VERSION 5.7 ;
  NOWIREEXTENSIONATPIN ON ;
  DIVIDERCHAR "/" ;
  BUSBITCHARS "[]" ;
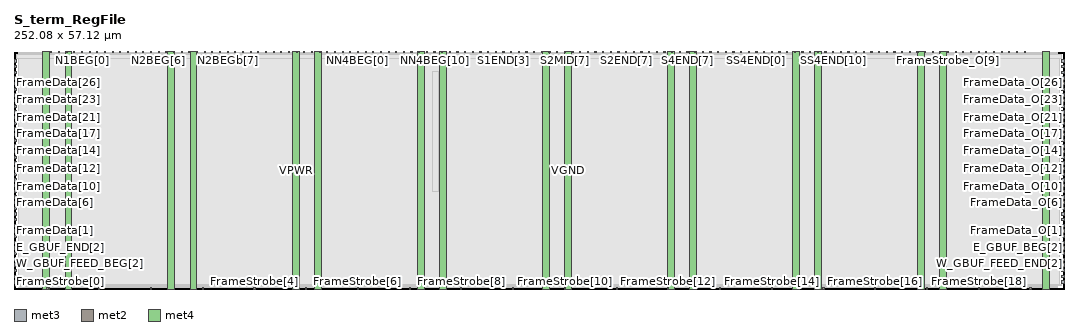
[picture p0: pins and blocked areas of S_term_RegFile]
MACRO S_term_RegFile
  CLASS BLOCK ;
  FOREIGN S_term_RegFile ;
  ORIGIN 0.000 0.000 ;
  SIZE 252.080 BY 57.120 ;
  PIN E_GBUF_BEG[0]
    DIRECTION OUTPUT ;
    USE SIGNAL ;
    ANTENNADIFFAREA 0.702900 ;
    PORT
      LAYER met3 ;
        RECT 251.480 6.840 252.080 7.440 ;
    END
  END E_GBUF_BEG[0]
  PIN E_GBUF_BEG[1]
    DIRECTION OUTPUT ;
    USE SIGNAL ;
    ANTENNADIFFAREA 0.702900 ;
    PORT
      LAYER met3 ;
        RECT 251.480 8.200 252.080 8.800 ;
    END
  END E_GBUF_BEG[1]
  PIN E_GBUF_BEG[2]
    DIRECTION OUTPUT ;
    USE SIGNAL ;
    ANTENNADIFFAREA 0.702900 ;
    PORT
      LAYER met3 ;
        RECT 251.480 9.560 252.080 10.160 ;
    END
  END E_GBUF_BEG[2]
  PIN E_GBUF_BEG[3]
    DIRECTION OUTPUT ;
    USE SIGNAL ;
    ANTENNADIFFAREA 0.702900 ;
    PORT
      LAYER met3 ;
        RECT 251.480 10.920 252.080 11.520 ;
    END
  END E_GBUF_BEG[3]
  PIN E_GBUF_END[0]
    DIRECTION INPUT ;
    USE SIGNAL ;
    ANTENNAGATEAREA 0.318000 ;
    PORT
      LAYER met3 ;
        RECT 0.000 6.840 0.600 7.440 ;
    END
  END E_GBUF_END[0]
  PIN E_GBUF_END[1]
    DIRECTION INPUT ;
    USE SIGNAL ;
    ANTENNAGATEAREA 0.318000 ;
    PORT
      LAYER met3 ;
        RECT 0.000 8.200 0.600 8.800 ;
    END
  END E_GBUF_END[1]
  PIN E_GBUF_END[2]
    DIRECTION INPUT ;
    USE SIGNAL ;
    ANTENNAGATEAREA 0.318000 ;
    PORT
      LAYER met3 ;
        RECT 0.000 9.560 0.600 10.160 ;
    END
  END E_GBUF_END[2]
  PIN E_GBUF_END[3]
    DIRECTION INPUT ;
    USE SIGNAL ;
    ANTENNAGATEAREA 0.318000 ;
    PORT
      LAYER met3 ;
        RECT 0.000 10.920 0.600 11.520 ;
    END
  END E_GBUF_END[3]
  PIN FrameData[0]
    DIRECTION INPUT ;
    USE SIGNAL ;
    ANTENNAGATEAREA 0.159000 ;
    PORT
      LAYER met3 ;
        RECT 0.000 12.280 0.600 12.880 ;
    END
  END FrameData[0]
  PIN FrameData[10]
    DIRECTION INPUT ;
    USE SIGNAL ;
    ANTENNAGATEAREA 0.159000 ;
    PORT
      LAYER met3 ;
        RECT 0.000 25.880 0.600 26.480 ;
    END
  END FrameData[10]
  PIN FrameData[11]
    DIRECTION INPUT ;
    USE SIGNAL ;
    ANTENNAGATEAREA 0.159000 ;
    PORT
      LAYER met3 ;
        RECT 0.000 27.240 0.600 27.840 ;
    END
  END FrameData[11]
  PIN FrameData[12]
    DIRECTION INPUT ;
    USE SIGNAL ;
    ANTENNAGATEAREA 0.159000 ;
    PORT
      LAYER met3 ;
        RECT 0.000 28.600 0.600 29.200 ;
    END
  END FrameData[12]
  PIN FrameData[13]
    DIRECTION INPUT ;
    USE SIGNAL ;
    ANTENNAGATEAREA 0.159000 ;
    PORT
      LAYER met3 ;
        RECT 0.000 29.960 0.600 30.560 ;
    END
  END FrameData[13]
  PIN FrameData[14]
    DIRECTION INPUT ;
    USE SIGNAL ;
    ANTENNAGATEAREA 0.159000 ;
    PORT
      LAYER met3 ;
        RECT 0.000 31.320 0.600 31.920 ;
    END
  END FrameData[14]
  PIN FrameData[15]
    DIRECTION INPUT ;
    USE SIGNAL ;
    ANTENNAGATEAREA 0.159000 ;
    PORT
      LAYER met3 ;
        RECT 0.000 32.680 0.600 33.280 ;
    END
  END FrameData[15]
  PIN FrameData[16]
    DIRECTION INPUT ;
    USE SIGNAL ;
    ANTENNAGATEAREA 0.159000 ;
    PORT
      LAYER met3 ;
        RECT 0.000 34.040 0.600 34.640 ;
    END
  END FrameData[16]
  PIN FrameData[17]
    DIRECTION INPUT ;
    USE SIGNAL ;
    ANTENNAGATEAREA 0.159000 ;
    PORT
      LAYER met3 ;
        RECT 0.000 35.400 0.600 36.000 ;
    END
  END FrameData[17]
  PIN FrameData[18]
    DIRECTION INPUT ;
    USE SIGNAL ;
    ANTENNAGATEAREA 0.159000 ;
    PORT
      LAYER met3 ;
        RECT 0.000 36.760 0.600 37.360 ;
    END
  END FrameData[18]
  PIN FrameData[19]
    DIRECTION INPUT ;
    USE SIGNAL ;
    ANTENNAGATEAREA 0.159000 ;
    PORT
      LAYER met3 ;
        RECT 0.000 38.120 0.600 38.720 ;
    END
  END FrameData[19]
  PIN FrameData[1]
    DIRECTION INPUT ;
    USE SIGNAL ;
    ANTENNAGATEAREA 0.159000 ;
    PORT
      LAYER met3 ;
        RECT 0.000 13.640 0.600 14.240 ;
    END
  END FrameData[1]
  PIN FrameData[20]
    DIRECTION INPUT ;
    USE SIGNAL ;
    ANTENNAGATEAREA 0.159000 ;
    PORT
      LAYER met3 ;
        RECT 0.000 39.480 0.600 40.080 ;
    END
  END FrameData[20]
  PIN FrameData[21]
    DIRECTION INPUT ;
    USE SIGNAL ;
    ANTENNAGATEAREA 0.159000 ;
    PORT
      LAYER met3 ;
        RECT 0.000 40.840 0.600 41.440 ;
    END
  END FrameData[21]
  PIN FrameData[22]
    DIRECTION INPUT ;
    USE SIGNAL ;
    ANTENNAGATEAREA 0.159000 ;
    PORT
      LAYER met3 ;
        RECT 0.000 42.200 0.600 42.800 ;
    END
  END FrameData[22]
  PIN FrameData[23]
    DIRECTION INPUT ;
    USE SIGNAL ;
    ANTENNAGATEAREA 0.159000 ;
    PORT
      LAYER met3 ;
        RECT 0.000 43.560 0.600 44.160 ;
    END
  END FrameData[23]
  PIN FrameData[24]
    DIRECTION INPUT ;
    USE SIGNAL ;
    ANTENNAGATEAREA 1.187400 ;
    ANTENNADIFFAREA 0.869400 ;
    PORT
      LAYER met3 ;
        RECT 0.000 44.920 0.600 45.520 ;
    END
  END FrameData[24]
  PIN FrameData[25]
    DIRECTION INPUT ;
    USE SIGNAL ;
    ANTENNAGATEAREA 1.187400 ;
    ANTENNADIFFAREA 0.869400 ;
    PORT
      LAYER met3 ;
        RECT 0.000 46.280 0.600 46.880 ;
    END
  END FrameData[25]
  PIN FrameData[26]
    DIRECTION INPUT ;
    USE SIGNAL ;
    ANTENNAGATEAREA 1.187400 ;
    ANTENNADIFFAREA 0.869400 ;
    PORT
      LAYER met3 ;
        RECT 0.000 47.640 0.600 48.240 ;
    END
  END FrameData[26]
  PIN FrameData[27]
    DIRECTION INPUT ;
    USE SIGNAL ;
    ANTENNAGATEAREA 1.187400 ;
    ANTENNADIFFAREA 0.869400 ;
    PORT
      LAYER met3 ;
        RECT 0.000 49.000 0.600 49.600 ;
    END
  END FrameData[27]
  PIN FrameData[28]
    DIRECTION INPUT ;
    USE SIGNAL ;
    ANTENNAGATEAREA 1.187400 ;
    ANTENNADIFFAREA 0.869400 ;
    PORT
      LAYER met3 ;
        RECT 0.000 50.360 0.600 50.960 ;
    END
  END FrameData[28]
  PIN FrameData[29]
    DIRECTION INPUT ;
    USE SIGNAL ;
    ANTENNAGATEAREA 1.187400 ;
    ANTENNADIFFAREA 0.869400 ;
    PORT
      LAYER met3 ;
        RECT 0.000 51.720 0.600 52.320 ;
    END
  END FrameData[29]
  PIN FrameData[2]
    DIRECTION INPUT ;
    USE SIGNAL ;
    ANTENNAGATEAREA 0.159000 ;
    PORT
      LAYER met3 ;
        RECT 0.000 15.000 0.600 15.600 ;
    END
  END FrameData[2]
  PIN FrameData[30]
    DIRECTION INPUT ;
    USE SIGNAL ;
    ANTENNAGATEAREA 0.318000 ;
    PORT
      LAYER met3 ;
        RECT 0.000 53.080 0.600 53.680 ;
    END
  END FrameData[30]
  PIN FrameData[31]
    DIRECTION INPUT ;
    USE SIGNAL ;
    ANTENNAGATEAREA 0.752700 ;
    ANTENNADIFFAREA 0.434700 ;
    PORT
      LAYER met3 ;
        RECT 0.000 54.440 0.600 55.040 ;
    END
  END FrameData[31]
  PIN FrameData[3]
    DIRECTION INPUT ;
    USE SIGNAL ;
    ANTENNAGATEAREA 0.159000 ;
    PORT
      LAYER met3 ;
        RECT 0.000 16.360 0.600 16.960 ;
    END
  END FrameData[3]
  PIN FrameData[4]
    DIRECTION INPUT ;
    USE SIGNAL ;
    ANTENNAGATEAREA 0.159000 ;
    PORT
      LAYER met3 ;
        RECT 0.000 17.720 0.600 18.320 ;
    END
  END FrameData[4]
  PIN FrameData[5]
    DIRECTION INPUT ;
    USE SIGNAL ;
    ANTENNAGATEAREA 0.159000 ;
    PORT
      LAYER met3 ;
        RECT 0.000 19.080 0.600 19.680 ;
    END
  END FrameData[5]
  PIN FrameData[6]
    DIRECTION INPUT ;
    USE SIGNAL ;
    ANTENNAGATEAREA 0.159000 ;
    PORT
      LAYER met3 ;
        RECT 0.000 20.440 0.600 21.040 ;
    END
  END FrameData[6]
  PIN FrameData[7]
    DIRECTION INPUT ;
    USE SIGNAL ;
    ANTENNAGATEAREA 0.159000 ;
    PORT
      LAYER met3 ;
        RECT 0.000 21.800 0.600 22.400 ;
    END
  END FrameData[7]
  PIN FrameData[8]
    DIRECTION INPUT ;
    USE SIGNAL ;
    ANTENNAGATEAREA 0.159000 ;
    PORT
      LAYER met3 ;
        RECT 0.000 23.160 0.600 23.760 ;
    END
  END FrameData[8]
  PIN FrameData[9]
    DIRECTION INPUT ;
    USE SIGNAL ;
    ANTENNAGATEAREA 0.159000 ;
    PORT
      LAYER met3 ;
        RECT 0.000 24.520 0.600 25.120 ;
    END
  END FrameData[9]
  PIN FrameData_O[0]
    DIRECTION OUTPUT ;
    USE SIGNAL ;
    ANTENNADIFFAREA 0.702900 ;
    PORT
      LAYER met3 ;
        RECT 251.480 12.280 252.080 12.880 ;
    END
  END FrameData_O[0]
  PIN FrameData_O[10]
    DIRECTION OUTPUT ;
    USE SIGNAL ;
    ANTENNADIFFAREA 0.702900 ;
    PORT
      LAYER met3 ;
        RECT 251.480 25.880 252.080 26.480 ;
    END
  END FrameData_O[10]
  PIN FrameData_O[11]
    DIRECTION OUTPUT ;
    USE SIGNAL ;
    ANTENNADIFFAREA 0.702900 ;
    PORT
      LAYER met3 ;
        RECT 251.480 27.240 252.080 27.840 ;
    END
  END FrameData_O[11]
  PIN FrameData_O[12]
    DIRECTION OUTPUT ;
    USE SIGNAL ;
    ANTENNADIFFAREA 0.702900 ;
    PORT
      LAYER met3 ;
        RECT 251.480 28.600 252.080 29.200 ;
    END
  END FrameData_O[12]
  PIN FrameData_O[13]
    DIRECTION OUTPUT ;
    USE SIGNAL ;
    ANTENNADIFFAREA 0.702900 ;
    PORT
      LAYER met3 ;
        RECT 251.480 29.960 252.080 30.560 ;
    END
  END FrameData_O[13]
  PIN FrameData_O[14]
    DIRECTION OUTPUT ;
    USE SIGNAL ;
    ANTENNADIFFAREA 0.702900 ;
    PORT
      LAYER met3 ;
        RECT 251.480 31.320 252.080 31.920 ;
    END
  END FrameData_O[14]
  PIN FrameData_O[15]
    DIRECTION OUTPUT ;
    USE SIGNAL ;
    ANTENNADIFFAREA 0.702900 ;
    PORT
      LAYER met3 ;
        RECT 251.480 32.680 252.080 33.280 ;
    END
  END FrameData_O[15]
  PIN FrameData_O[16]
    DIRECTION OUTPUT ;
    USE SIGNAL ;
    ANTENNADIFFAREA 0.702900 ;
    PORT
      LAYER met3 ;
        RECT 251.480 34.040 252.080 34.640 ;
    END
  END FrameData_O[16]
  PIN FrameData_O[17]
    DIRECTION OUTPUT ;
    USE SIGNAL ;
    ANTENNADIFFAREA 0.702900 ;
    PORT
      LAYER met3 ;
        RECT 251.480 35.400 252.080 36.000 ;
    END
  END FrameData_O[17]
  PIN FrameData_O[18]
    DIRECTION OUTPUT ;
    USE SIGNAL ;
    ANTENNADIFFAREA 0.702900 ;
    PORT
      LAYER met3 ;
        RECT 251.480 36.760 252.080 37.360 ;
    END
  END FrameData_O[18]
  PIN FrameData_O[19]
    DIRECTION OUTPUT ;
    USE SIGNAL ;
    ANTENNADIFFAREA 0.702900 ;
    PORT
      LAYER met3 ;
        RECT 251.480 38.120 252.080 38.720 ;
    END
  END FrameData_O[19]
  PIN FrameData_O[1]
    DIRECTION OUTPUT ;
    USE SIGNAL ;
    ANTENNADIFFAREA 0.702900 ;
    PORT
      LAYER met3 ;
        RECT 251.480 13.640 252.080 14.240 ;
    END
  END FrameData_O[1]
  PIN FrameData_O[20]
    DIRECTION OUTPUT ;
    USE SIGNAL ;
    ANTENNADIFFAREA 0.702900 ;
    PORT
      LAYER met3 ;
        RECT 251.480 39.480 252.080 40.080 ;
    END
  END FrameData_O[20]
  PIN FrameData_O[21]
    DIRECTION OUTPUT ;
    USE SIGNAL ;
    ANTENNADIFFAREA 0.702900 ;
    PORT
      LAYER met3 ;
        RECT 251.480 40.840 252.080 41.440 ;
    END
  END FrameData_O[21]
  PIN FrameData_O[22]
    DIRECTION OUTPUT ;
    USE SIGNAL ;
    ANTENNADIFFAREA 0.702900 ;
    PORT
      LAYER met3 ;
        RECT 251.480 42.200 252.080 42.800 ;
    END
  END FrameData_O[22]
  PIN FrameData_O[23]
    DIRECTION OUTPUT ;
    USE SIGNAL ;
    ANTENNADIFFAREA 0.702900 ;
    PORT
      LAYER met3 ;
        RECT 251.480 43.560 252.080 44.160 ;
    END
  END FrameData_O[23]
  PIN FrameData_O[24]
    DIRECTION OUTPUT ;
    USE SIGNAL ;
    ANTENNADIFFAREA 0.702900 ;
    PORT
      LAYER met3 ;
        RECT 251.480 44.920 252.080 45.520 ;
    END
  END FrameData_O[24]
  PIN FrameData_O[25]
    DIRECTION OUTPUT ;
    USE SIGNAL ;
    ANTENNADIFFAREA 0.702900 ;
    PORT
      LAYER met3 ;
        RECT 251.480 46.280 252.080 46.880 ;
    END
  END FrameData_O[25]
  PIN FrameData_O[26]
    DIRECTION OUTPUT ;
    USE SIGNAL ;
    ANTENNADIFFAREA 0.702900 ;
    PORT
      LAYER met3 ;
        RECT 251.480 47.640 252.080 48.240 ;
    END
  END FrameData_O[26]
  PIN FrameData_O[27]
    DIRECTION OUTPUT ;
    USE SIGNAL ;
    ANTENNADIFFAREA 0.702900 ;
    PORT
      LAYER met3 ;
        RECT 251.480 49.000 252.080 49.600 ;
    END
  END FrameData_O[27]
  PIN FrameData_O[28]
    DIRECTION OUTPUT ;
    USE SIGNAL ;
    ANTENNADIFFAREA 0.702900 ;
    PORT
      LAYER met3 ;
        RECT 251.480 50.360 252.080 50.960 ;
    END
  END FrameData_O[28]
  PIN FrameData_O[29]
    DIRECTION OUTPUT ;
    USE SIGNAL ;
    ANTENNADIFFAREA 0.702900 ;
    PORT
      LAYER met3 ;
        RECT 251.480 51.720 252.080 52.320 ;
    END
  END FrameData_O[29]
  PIN FrameData_O[2]
    DIRECTION OUTPUT ;
    USE SIGNAL ;
    ANTENNADIFFAREA 0.702900 ;
    PORT
      LAYER met3 ;
        RECT 251.480 15.000 252.080 15.600 ;
    END
  END FrameData_O[2]
  PIN FrameData_O[30]
    DIRECTION OUTPUT ;
    USE SIGNAL ;
    ANTENNADIFFAREA 0.702900 ;
    PORT
      LAYER met3 ;
        RECT 251.480 53.080 252.080 53.680 ;
    END
  END FrameData_O[30]
  PIN FrameData_O[31]
    DIRECTION OUTPUT ;
    USE SIGNAL ;
    ANTENNADIFFAREA 0.702900 ;
    PORT
      LAYER met3 ;
        RECT 251.480 54.440 252.080 55.040 ;
    END
  END FrameData_O[31]
  PIN FrameData_O[3]
    DIRECTION OUTPUT ;
    USE SIGNAL ;
    ANTENNADIFFAREA 0.702900 ;
    PORT
      LAYER met3 ;
        RECT 251.480 16.360 252.080 16.960 ;
    END
  END FrameData_O[3]
  PIN FrameData_O[4]
    DIRECTION OUTPUT ;
    USE SIGNAL ;
    ANTENNADIFFAREA 0.702900 ;
    PORT
      LAYER met3 ;
        RECT 251.480 17.720 252.080 18.320 ;
    END
  END FrameData_O[4]
  PIN FrameData_O[5]
    DIRECTION OUTPUT ;
    USE SIGNAL ;
    ANTENNADIFFAREA 0.702900 ;
    PORT
      LAYER met3 ;
        RECT 251.480 19.080 252.080 19.680 ;
    END
  END FrameData_O[5]
  PIN FrameData_O[6]
    DIRECTION OUTPUT ;
    USE SIGNAL ;
    ANTENNADIFFAREA 0.702900 ;
    PORT
      LAYER met3 ;
        RECT 251.480 20.440 252.080 21.040 ;
    END
  END FrameData_O[6]
  PIN FrameData_O[7]
    DIRECTION OUTPUT ;
    USE SIGNAL ;
    ANTENNADIFFAREA 0.702900 ;
    PORT
      LAYER met3 ;
        RECT 251.480 21.800 252.080 22.400 ;
    END
  END FrameData_O[7]
  PIN FrameData_O[8]
    DIRECTION OUTPUT ;
    USE SIGNAL ;
    ANTENNADIFFAREA 0.702900 ;
    PORT
      LAYER met3 ;
        RECT 251.480 23.160 252.080 23.760 ;
    END
  END FrameData_O[8]
  PIN FrameData_O[9]
    DIRECTION OUTPUT ;
    USE SIGNAL ;
    ANTENNADIFFAREA 0.702900 ;
    PORT
      LAYER met3 ;
        RECT 251.480 24.520 252.080 25.120 ;
    END
  END FrameData_O[9]
  PIN FrameStrobe[0]
    DIRECTION INPUT ;
    USE SIGNAL ;
    ANTENNAGATEAREA 1.865700 ;
    ANTENNADIFFAREA 0.434700 ;
    PORT
      LAYER met2 ;
        RECT 7.910 0.000 8.190 0.280 ;
    END
  END FrameStrobe[0]
  PIN FrameStrobe[10]
    DIRECTION INPUT ;
    USE SIGNAL ;
    ANTENNAGATEAREA 0.159000 ;
    PORT
      LAYER met2 ;
        RECT 132.110 0.000 132.390 0.280 ;
    END
  END FrameStrobe[10]
  PIN FrameStrobe[11]
    DIRECTION INPUT ;
    USE SIGNAL ;
    ANTENNAGATEAREA 0.159000 ;
    PORT
      LAYER met2 ;
        RECT 144.530 0.000 144.810 0.280 ;
    END
  END FrameStrobe[11]
  PIN FrameStrobe[12]
    DIRECTION INPUT ;
    USE SIGNAL ;
    ANTENNAGATEAREA 0.159000 ;
    PORT
      LAYER met2 ;
        RECT 156.950 0.000 157.230 0.280 ;
    END
  END FrameStrobe[12]
  PIN FrameStrobe[13]
    DIRECTION INPUT ;
    USE SIGNAL ;
    ANTENNAGATEAREA 0.159000 ;
    PORT
      LAYER met2 ;
        RECT 169.370 0.000 169.650 0.280 ;
    END
  END FrameStrobe[13]
  PIN FrameStrobe[14]
    DIRECTION INPUT ;
    USE SIGNAL ;
    ANTENNAGATEAREA 0.159000 ;
    PORT
      LAYER met2 ;
        RECT 181.790 0.000 182.070 0.280 ;
    END
  END FrameStrobe[14]
  PIN FrameStrobe[15]
    DIRECTION INPUT ;
    USE SIGNAL ;
    ANTENNAGATEAREA 0.159000 ;
    PORT
      LAYER met2 ;
        RECT 194.210 0.000 194.490 0.280 ;
    END
  END FrameStrobe[15]
  PIN FrameStrobe[16]
    DIRECTION INPUT ;
    USE SIGNAL ;
    ANTENNAGATEAREA 0.159000 ;
    PORT
      LAYER met2 ;
        RECT 206.630 0.000 206.910 0.280 ;
    END
  END FrameStrobe[16]
  PIN FrameStrobe[17]
    DIRECTION INPUT ;
    USE SIGNAL ;
    ANTENNAGATEAREA 0.159000 ;
    PORT
      LAYER met2 ;
        RECT 219.050 0.000 219.330 0.280 ;
    END
  END FrameStrobe[17]
  PIN FrameStrobe[18]
    DIRECTION INPUT ;
    USE SIGNAL ;
    ANTENNAGATEAREA 0.159000 ;
    PORT
      LAYER met2 ;
        RECT 231.470 0.000 231.750 0.280 ;
    END
  END FrameStrobe[18]
  PIN FrameStrobe[19]
    DIRECTION INPUT ;
    USE SIGNAL ;
    ANTENNAGATEAREA 0.159000 ;
    PORT
      LAYER met2 ;
        RECT 243.890 0.000 244.170 0.280 ;
    END
  END FrameStrobe[19]
  PIN FrameStrobe[1]
    DIRECTION INPUT ;
    USE SIGNAL ;
    ANTENNAGATEAREA 0.159000 ;
    PORT
      LAYER met2 ;
        RECT 20.330 0.000 20.610 0.280 ;
    END
  END FrameStrobe[1]
  PIN FrameStrobe[2]
    DIRECTION INPUT ;
    USE SIGNAL ;
    ANTENNAGATEAREA 0.159000 ;
    PORT
      LAYER met2 ;
        RECT 32.750 0.000 33.030 0.280 ;
    END
  END FrameStrobe[2]
  PIN FrameStrobe[3]
    DIRECTION INPUT ;
    USE SIGNAL ;
    ANTENNAGATEAREA 0.159000 ;
    PORT
      LAYER met2 ;
        RECT 45.170 0.000 45.450 0.280 ;
    END
  END FrameStrobe[3]
  PIN FrameStrobe[4]
    DIRECTION INPUT ;
    USE SIGNAL ;
    ANTENNAGATEAREA 0.593700 ;
    ANTENNADIFFAREA 0.434700 ;
    PORT
      LAYER met2 ;
        RECT 57.590 0.000 57.870 0.280 ;
    END
  END FrameStrobe[4]
  PIN FrameStrobe[5]
    DIRECTION INPUT ;
    USE SIGNAL ;
    ANTENNAGATEAREA 0.159000 ;
    PORT
      LAYER met2 ;
        RECT 70.010 0.000 70.290 0.280 ;
    END
  END FrameStrobe[5]
  PIN FrameStrobe[6]
    DIRECTION INPUT ;
    USE SIGNAL ;
    ANTENNAGATEAREA 0.593700 ;
    ANTENNADIFFAREA 0.434700 ;
    PORT
      LAYER met2 ;
        RECT 82.430 0.000 82.710 0.280 ;
    END
  END FrameStrobe[6]
  PIN FrameStrobe[7]
    DIRECTION INPUT ;
    USE SIGNAL ;
    ANTENNAGATEAREA 0.593700 ;
    ANTENNADIFFAREA 0.434700 ;
    PORT
      LAYER met2 ;
        RECT 94.850 0.000 95.130 0.280 ;
    END
  END FrameStrobe[7]
  PIN FrameStrobe[8]
    DIRECTION INPUT ;
    USE SIGNAL ;
    ANTENNAGATEAREA 0.593700 ;
    ANTENNADIFFAREA 0.434700 ;
    PORT
      LAYER met2 ;
        RECT 107.270 0.000 107.550 0.280 ;
    END
  END FrameStrobe[8]
  PIN FrameStrobe[9]
    DIRECTION INPUT ;
    USE SIGNAL ;
    ANTENNAGATEAREA 0.593700 ;
    ANTENNADIFFAREA 0.434700 ;
    PORT
      LAYER met2 ;
        RECT 119.690 0.000 119.970 0.280 ;
    END
  END FrameStrobe[9]
  PIN FrameStrobe_O[0]
    DIRECTION OUTPUT ;
    USE SIGNAL ;
    ANTENNADIFFAREA 0.702900 ;
    PORT
      LAYER met2 ;
        RECT 207.550 56.840 207.830 57.120 ;
    END
  END FrameStrobe_O[0]
  PIN FrameStrobe_O[10]
    DIRECTION OUTPUT ;
    USE SIGNAL ;
    ANTENNADIFFAREA 0.702900 ;
    PORT
      LAYER met2 ;
        RECT 225.950 56.840 226.230 57.120 ;
    END
  END FrameStrobe_O[10]
  PIN FrameStrobe_O[11]
    DIRECTION OUTPUT ;
    USE SIGNAL ;
    ANTENNADIFFAREA 0.702900 ;
    PORT
      LAYER met2 ;
        RECT 227.790 56.840 228.070 57.120 ;
    END
  END FrameStrobe_O[11]
  PIN FrameStrobe_O[12]
    DIRECTION OUTPUT ;
    USE SIGNAL ;
    ANTENNADIFFAREA 0.702900 ;
    PORT
      LAYER met2 ;
        RECT 229.630 56.840 229.910 57.120 ;
    END
  END FrameStrobe_O[12]
  PIN FrameStrobe_O[13]
    DIRECTION OUTPUT ;
    USE SIGNAL ;
    ANTENNADIFFAREA 0.702900 ;
    PORT
      LAYER met2 ;
        RECT 231.470 56.840 231.750 57.120 ;
    END
  END FrameStrobe_O[13]
  PIN FrameStrobe_O[14]
    DIRECTION OUTPUT ;
    USE SIGNAL ;
    ANTENNADIFFAREA 0.702900 ;
    PORT
      LAYER met2 ;
        RECT 233.310 56.840 233.590 57.120 ;
    END
  END FrameStrobe_O[14]
  PIN FrameStrobe_O[15]
    DIRECTION OUTPUT ;
    USE SIGNAL ;
    ANTENNADIFFAREA 0.702900 ;
    PORT
      LAYER met2 ;
        RECT 235.150 56.840 235.430 57.120 ;
    END
  END FrameStrobe_O[15]
  PIN FrameStrobe_O[16]
    DIRECTION OUTPUT ;
    USE SIGNAL ;
    ANTENNADIFFAREA 0.702900 ;
    PORT
      LAYER met2 ;
        RECT 236.990 56.840 237.270 57.120 ;
    END
  END FrameStrobe_O[16]
  PIN FrameStrobe_O[17]
    DIRECTION OUTPUT ;
    USE SIGNAL ;
    ANTENNADIFFAREA 0.702900 ;
    PORT
      LAYER met2 ;
        RECT 238.830 56.840 239.110 57.120 ;
    END
  END FrameStrobe_O[17]
  PIN FrameStrobe_O[18]
    DIRECTION OUTPUT ;
    USE SIGNAL ;
    ANTENNADIFFAREA 0.702900 ;
    PORT
      LAYER met2 ;
        RECT 240.670 56.840 240.950 57.120 ;
    END
  END FrameStrobe_O[18]
  PIN FrameStrobe_O[19]
    DIRECTION OUTPUT ;
    USE SIGNAL ;
    ANTENNADIFFAREA 0.702900 ;
    PORT
      LAYER met2 ;
        RECT 242.510 56.840 242.790 57.120 ;
    END
  END FrameStrobe_O[19]
  PIN FrameStrobe_O[1]
    DIRECTION OUTPUT ;
    USE SIGNAL ;
    ANTENNADIFFAREA 0.702900 ;
    PORT
      LAYER met2 ;
        RECT 209.390 56.840 209.670 57.120 ;
    END
  END FrameStrobe_O[1]
  PIN FrameStrobe_O[2]
    DIRECTION OUTPUT ;
    USE SIGNAL ;
    ANTENNADIFFAREA 0.702900 ;
    PORT
      LAYER met2 ;
        RECT 211.230 56.840 211.510 57.120 ;
    END
  END FrameStrobe_O[2]
  PIN FrameStrobe_O[3]
    DIRECTION OUTPUT ;
    USE SIGNAL ;
    ANTENNADIFFAREA 0.702900 ;
    PORT
      LAYER met2 ;
        RECT 213.070 56.840 213.350 57.120 ;
    END
  END FrameStrobe_O[3]
  PIN FrameStrobe_O[4]
    DIRECTION OUTPUT ;
    USE SIGNAL ;
    ANTENNADIFFAREA 0.702900 ;
    PORT
      LAYER met2 ;
        RECT 214.910 56.840 215.190 57.120 ;
    END
  END FrameStrobe_O[4]
  PIN FrameStrobe_O[5]
    DIRECTION OUTPUT ;
    USE SIGNAL ;
    ANTENNADIFFAREA 0.702900 ;
    PORT
      LAYER met2 ;
        RECT 216.750 56.840 217.030 57.120 ;
    END
  END FrameStrobe_O[5]
  PIN FrameStrobe_O[6]
    DIRECTION OUTPUT ;
    USE SIGNAL ;
    ANTENNADIFFAREA 0.702900 ;
    PORT
      LAYER met2 ;
        RECT 218.590 56.840 218.870 57.120 ;
    END
  END FrameStrobe_O[6]
  PIN FrameStrobe_O[7]
    DIRECTION OUTPUT ;
    USE SIGNAL ;
    ANTENNADIFFAREA 0.702900 ;
    PORT
      LAYER met2 ;
        RECT 220.430 56.840 220.710 57.120 ;
    END
  END FrameStrobe_O[7]
  PIN FrameStrobe_O[8]
    DIRECTION OUTPUT ;
    USE SIGNAL ;
    ANTENNADIFFAREA 0.702900 ;
    PORT
      LAYER met2 ;
        RECT 222.270 56.840 222.550 57.120 ;
    END
  END FrameStrobe_O[8]
  PIN FrameStrobe_O[9]
    DIRECTION OUTPUT ;
    USE SIGNAL ;
    ANTENNADIFFAREA 0.702900 ;
    PORT
      LAYER met2 ;
        RECT 224.110 56.840 224.390 57.120 ;
    END
  END FrameStrobe_O[9]
  PIN N1BEG[0]
    DIRECTION OUTPUT ;
    USE SIGNAL ;
    ANTENNADIFFAREA 0.702900 ;
    PORT
      LAYER met2 ;
        RECT 16.190 56.840 16.470 57.120 ;
    END
  END N1BEG[0]
  PIN N1BEG[1]
    DIRECTION OUTPUT ;
    USE SIGNAL ;
    ANTENNADIFFAREA 0.702900 ;
    PORT
      LAYER met2 ;
        RECT 18.030 56.840 18.310 57.120 ;
    END
  END N1BEG[1]
  PIN N1BEG[2]
    DIRECTION OUTPUT ;
    USE SIGNAL ;
    ANTENNADIFFAREA 0.702900 ;
    PORT
      LAYER met2 ;
        RECT 19.870 56.840 20.150 57.120 ;
    END
  END N1BEG[2]
  PIN N1BEG[3]
    DIRECTION OUTPUT ;
    USE SIGNAL ;
    ANTENNADIFFAREA 0.702900 ;
    PORT
      LAYER met2 ;
        RECT 21.710 56.840 21.990 57.120 ;
    END
  END N1BEG[3]
  PIN N2BEG[0]
    DIRECTION OUTPUT ;
    USE SIGNAL ;
    ANTENNADIFFAREA 0.702900 ;
    PORT
      LAYER met2 ;
        RECT 23.550 56.840 23.830 57.120 ;
    END
  END N2BEG[0]
  PIN N2BEG[1]
    DIRECTION OUTPUT ;
    USE SIGNAL ;
    ANTENNADIFFAREA 0.702900 ;
    PORT
      LAYER met2 ;
        RECT 25.390 56.840 25.670 57.120 ;
    END
  END N2BEG[1]
  PIN N2BEG[2]
    DIRECTION OUTPUT ;
    USE SIGNAL ;
    ANTENNADIFFAREA 0.702900 ;
    PORT
      LAYER met2 ;
        RECT 27.230 56.840 27.510 57.120 ;
    END
  END N2BEG[2]
  PIN N2BEG[3]
    DIRECTION OUTPUT ;
    USE SIGNAL ;
    ANTENNADIFFAREA 0.702900 ;
    PORT
      LAYER met2 ;
        RECT 29.070 56.840 29.350 57.120 ;
    END
  END N2BEG[3]
  PIN N2BEG[4]
    DIRECTION OUTPUT ;
    USE SIGNAL ;
    ANTENNADIFFAREA 0.702900 ;
    PORT
      LAYER met2 ;
        RECT 30.910 56.840 31.190 57.120 ;
    END
  END N2BEG[4]
  PIN N2BEG[5]
    DIRECTION OUTPUT ;
    USE SIGNAL ;
    ANTENNADIFFAREA 0.702900 ;
    PORT
      LAYER met2 ;
        RECT 32.750 56.840 33.030 57.120 ;
    END
  END N2BEG[5]
  PIN N2BEG[6]
    DIRECTION OUTPUT ;
    USE SIGNAL ;
    ANTENNADIFFAREA 0.702900 ;
    PORT
      LAYER met2 ;
        RECT 34.590 56.840 34.870 57.120 ;
    END
  END N2BEG[6]
  PIN N2BEG[7]
    DIRECTION OUTPUT ;
    USE SIGNAL ;
    ANTENNADIFFAREA 0.702900 ;
    PORT
      LAYER met2 ;
        RECT 36.430 56.840 36.710 57.120 ;
    END
  END N2BEG[7]
  PIN N2BEGb[0]
    DIRECTION OUTPUT ;
    USE SIGNAL ;
    ANTENNADIFFAREA 0.702900 ;
    PORT
      LAYER met2 ;
        RECT 38.270 56.840 38.550 57.120 ;
    END
  END N2BEGb[0]
  PIN N2BEGb[1]
    DIRECTION OUTPUT ;
    USE SIGNAL ;
    ANTENNADIFFAREA 0.702900 ;
    PORT
      LAYER met2 ;
        RECT 40.110 56.840 40.390 57.120 ;
    END
  END N2BEGb[1]
  PIN N2BEGb[2]
    DIRECTION OUTPUT ;
    USE SIGNAL ;
    ANTENNADIFFAREA 0.702900 ;
    PORT
      LAYER met2 ;
        RECT 41.950 56.840 42.230 57.120 ;
    END
  END N2BEGb[2]
  PIN N2BEGb[3]
    DIRECTION OUTPUT ;
    USE SIGNAL ;
    ANTENNADIFFAREA 0.702900 ;
    PORT
      LAYER met2 ;
        RECT 43.790 56.840 44.070 57.120 ;
    END
  END N2BEGb[3]
  PIN N2BEGb[4]
    DIRECTION OUTPUT ;
    USE SIGNAL ;
    ANTENNADIFFAREA 0.702900 ;
    PORT
      LAYER met2 ;
        RECT 45.630 56.840 45.910 57.120 ;
    END
  END N2BEGb[4]
  PIN N2BEGb[5]
    DIRECTION OUTPUT ;
    USE SIGNAL ;
    ANTENNADIFFAREA 0.702900 ;
    PORT
      LAYER met2 ;
        RECT 47.470 56.840 47.750 57.120 ;
    END
  END N2BEGb[5]
  PIN N2BEGb[6]
    DIRECTION OUTPUT ;
    USE SIGNAL ;
    ANTENNADIFFAREA 0.702900 ;
    PORT
      LAYER met2 ;
        RECT 49.310 56.840 49.590 57.120 ;
    END
  END N2BEGb[6]
  PIN N2BEGb[7]
    DIRECTION OUTPUT ;
    USE SIGNAL ;
    ANTENNADIFFAREA 0.702900 ;
    PORT
      LAYER met2 ;
        RECT 51.150 56.840 51.430 57.120 ;
    END
  END N2BEGb[7]
  PIN N4BEG[0]
    DIRECTION OUTPUT ;
    USE SIGNAL ;
    ANTENNADIFFAREA 0.702900 ;
    PORT
      LAYER met2 ;
        RECT 52.990 56.840 53.270 57.120 ;
    END
  END N4BEG[0]
  PIN N4BEG[10]
    DIRECTION OUTPUT ;
    USE SIGNAL ;
    ANTENNADIFFAREA 0.702900 ;
    PORT
      LAYER met2 ;
        RECT 71.390 56.840 71.670 57.120 ;
    END
  END N4BEG[10]
  PIN N4BEG[11]
    DIRECTION OUTPUT ;
    USE SIGNAL ;
    ANTENNADIFFAREA 0.702900 ;
    PORT
      LAYER met2 ;
        RECT 73.230 56.840 73.510 57.120 ;
    END
  END N4BEG[11]
  PIN N4BEG[12]
    DIRECTION OUTPUT ;
    USE SIGNAL ;
    ANTENNADIFFAREA 0.702900 ;
    PORT
      LAYER met2 ;
        RECT 75.070 56.840 75.350 57.120 ;
    END
  END N4BEG[12]
  PIN N4BEG[13]
    DIRECTION OUTPUT ;
    USE SIGNAL ;
    ANTENNADIFFAREA 0.702900 ;
    PORT
      LAYER met2 ;
        RECT 76.910 56.840 77.190 57.120 ;
    END
  END N4BEG[13]
  PIN N4BEG[14]
    DIRECTION OUTPUT ;
    USE SIGNAL ;
    ANTENNADIFFAREA 0.702900 ;
    PORT
      LAYER met2 ;
        RECT 78.750 56.840 79.030 57.120 ;
    END
  END N4BEG[14]
  PIN N4BEG[15]
    DIRECTION OUTPUT ;
    USE SIGNAL ;
    ANTENNADIFFAREA 0.702900 ;
    PORT
      LAYER met2 ;
        RECT 80.590 56.840 80.870 57.120 ;
    END
  END N4BEG[15]
  PIN N4BEG[1]
    DIRECTION OUTPUT ;
    USE SIGNAL ;
    ANTENNADIFFAREA 0.702900 ;
    PORT
      LAYER met2 ;
        RECT 54.830 56.840 55.110 57.120 ;
    END
  END N4BEG[1]
  PIN N4BEG[2]
    DIRECTION OUTPUT ;
    USE SIGNAL ;
    ANTENNADIFFAREA 0.702900 ;
    PORT
      LAYER met2 ;
        RECT 56.670 56.840 56.950 57.120 ;
    END
  END N4BEG[2]
  PIN N4BEG[3]
    DIRECTION OUTPUT ;
    USE SIGNAL ;
    ANTENNADIFFAREA 0.702900 ;
    PORT
      LAYER met2 ;
        RECT 58.510 56.840 58.790 57.120 ;
    END
  END N4BEG[3]
  PIN N4BEG[4]
    DIRECTION OUTPUT ;
    USE SIGNAL ;
    ANTENNADIFFAREA 0.702900 ;
    PORT
      LAYER met2 ;
        RECT 60.350 56.840 60.630 57.120 ;
    END
  END N4BEG[4]
  PIN N4BEG[5]
    DIRECTION OUTPUT ;
    USE SIGNAL ;
    ANTENNADIFFAREA 0.702900 ;
    PORT
      LAYER met2 ;
        RECT 62.190 56.840 62.470 57.120 ;
    END
  END N4BEG[5]
  PIN N4BEG[6]
    DIRECTION OUTPUT ;
    USE SIGNAL ;
    ANTENNADIFFAREA 0.702900 ;
    PORT
      LAYER met2 ;
        RECT 64.030 56.840 64.310 57.120 ;
    END
  END N4BEG[6]
  PIN N4BEG[7]
    DIRECTION OUTPUT ;
    USE SIGNAL ;
    ANTENNADIFFAREA 0.702900 ;
    PORT
      LAYER met2 ;
        RECT 65.870 56.840 66.150 57.120 ;
    END
  END N4BEG[7]
  PIN N4BEG[8]
    DIRECTION OUTPUT ;
    USE SIGNAL ;
    ANTENNADIFFAREA 0.702900 ;
    PORT
      LAYER met2 ;
        RECT 67.710 56.840 67.990 57.120 ;
    END
  END N4BEG[8]
  PIN N4BEG[9]
    DIRECTION OUTPUT ;
    USE SIGNAL ;
    ANTENNADIFFAREA 0.702900 ;
    PORT
      LAYER met2 ;
        RECT 69.550 56.840 69.830 57.120 ;
    END
  END N4BEG[9]
  PIN NN4BEG[0]
    DIRECTION OUTPUT ;
    USE SIGNAL ;
    ANTENNADIFFAREA 0.702900 ;
    PORT
      LAYER met2 ;
        RECT 82.430 56.840 82.710 57.120 ;
    END
  END NN4BEG[0]
  PIN NN4BEG[10]
    DIRECTION OUTPUT ;
    USE SIGNAL ;
    ANTENNADIFFAREA 0.702900 ;
    PORT
      LAYER met2 ;
        RECT 100.830 56.840 101.110 57.120 ;
    END
  END NN4BEG[10]
  PIN NN4BEG[11]
    DIRECTION OUTPUT ;
    USE SIGNAL ;
    ANTENNADIFFAREA 0.702900 ;
    PORT
      LAYER met2 ;
        RECT 102.670 56.840 102.950 57.120 ;
    END
  END NN4BEG[11]
  PIN NN4BEG[12]
    DIRECTION OUTPUT ;
    USE SIGNAL ;
    ANTENNADIFFAREA 0.702900 ;
    PORT
      LAYER met2 ;
        RECT 104.510 56.840 104.790 57.120 ;
    END
  END NN4BEG[12]
  PIN NN4BEG[13]
    DIRECTION OUTPUT ;
    USE SIGNAL ;
    ANTENNADIFFAREA 0.702900 ;
    PORT
      LAYER met2 ;
        RECT 106.350 56.840 106.630 57.120 ;
    END
  END NN4BEG[13]
  PIN NN4BEG[14]
    DIRECTION OUTPUT ;
    USE SIGNAL ;
    ANTENNADIFFAREA 0.702900 ;
    PORT
      LAYER met2 ;
        RECT 108.190 56.840 108.470 57.120 ;
    END
  END NN4BEG[14]
  PIN NN4BEG[15]
    DIRECTION OUTPUT ;
    USE SIGNAL ;
    ANTENNADIFFAREA 0.702900 ;
    PORT
      LAYER met2 ;
        RECT 110.030 56.840 110.310 57.120 ;
    END
  END NN4BEG[15]
  PIN NN4BEG[1]
    DIRECTION OUTPUT ;
    USE SIGNAL ;
    ANTENNADIFFAREA 0.702900 ;
    PORT
      LAYER met2 ;
        RECT 84.270 56.840 84.550 57.120 ;
    END
  END NN4BEG[1]
  PIN NN4BEG[2]
    DIRECTION OUTPUT ;
    USE SIGNAL ;
    ANTENNADIFFAREA 0.702900 ;
    PORT
      LAYER met2 ;
        RECT 86.110 56.840 86.390 57.120 ;
    END
  END NN4BEG[2]
  PIN NN4BEG[3]
    DIRECTION OUTPUT ;
    USE SIGNAL ;
    ANTENNADIFFAREA 0.702900 ;
    PORT
      LAYER met2 ;
        RECT 87.950 56.840 88.230 57.120 ;
    END
  END NN4BEG[3]
  PIN NN4BEG[4]
    DIRECTION OUTPUT ;
    USE SIGNAL ;
    ANTENNADIFFAREA 0.702900 ;
    PORT
      LAYER met2 ;
        RECT 89.790 56.840 90.070 57.120 ;
    END
  END NN4BEG[4]
  PIN NN4BEG[5]
    DIRECTION OUTPUT ;
    USE SIGNAL ;
    ANTENNADIFFAREA 0.702900 ;
    PORT
      LAYER met2 ;
        RECT 91.630 56.840 91.910 57.120 ;
    END
  END NN4BEG[5]
  PIN NN4BEG[6]
    DIRECTION OUTPUT ;
    USE SIGNAL ;
    ANTENNADIFFAREA 0.702900 ;
    PORT
      LAYER met2 ;
        RECT 93.470 56.840 93.750 57.120 ;
    END
  END NN4BEG[6]
  PIN NN4BEG[7]
    DIRECTION OUTPUT ;
    USE SIGNAL ;
    ANTENNADIFFAREA 0.702900 ;
    PORT
      LAYER met2 ;
        RECT 95.310 56.840 95.590 57.120 ;
    END
  END NN4BEG[7]
  PIN NN4BEG[8]
    DIRECTION OUTPUT ;
    USE SIGNAL ;
    ANTENNADIFFAREA 0.702900 ;
    PORT
      LAYER met2 ;
        RECT 97.150 56.840 97.430 57.120 ;
    END
  END NN4BEG[8]
  PIN NN4BEG[9]
    DIRECTION OUTPUT ;
    USE SIGNAL ;
    ANTENNADIFFAREA 0.702900 ;
    PORT
      LAYER met2 ;
        RECT 98.990 56.840 99.270 57.120 ;
    END
  END NN4BEG[9]
  PIN N_GBUF_BEG[0]
    DIRECTION OUTPUT ;
    USE SIGNAL ;
    ANTENNADIFFAREA 0.702900 ;
    PORT
      LAYER met2 ;
        RECT 8.830 56.840 9.110 57.120 ;
    END
  END N_GBUF_BEG[0]
  PIN N_GBUF_BEG[1]
    DIRECTION OUTPUT ;
    USE SIGNAL ;
    ANTENNADIFFAREA 0.702900 ;
    PORT
      LAYER met2 ;
        RECT 10.670 56.840 10.950 57.120 ;
    END
  END N_GBUF_BEG[1]
  PIN N_GBUF_BEG[2]
    DIRECTION OUTPUT ;
    USE SIGNAL ;
    ANTENNADIFFAREA 0.702900 ;
    PORT
      LAYER met2 ;
        RECT 12.510 56.840 12.790 57.120 ;
    END
  END N_GBUF_BEG[2]
  PIN N_GBUF_BEG[3]
    DIRECTION OUTPUT ;
    USE SIGNAL ;
    ANTENNADIFFAREA 0.702900 ;
    PORT
      LAYER met2 ;
        RECT 14.350 56.840 14.630 57.120 ;
    END
  END N_GBUF_BEG[3]
  PIN S1END[0]
    DIRECTION INPUT ;
    USE SIGNAL ;
    ANTENNAGATEAREA 0.318000 ;
    PORT
      LAYER met2 ;
        RECT 111.870 56.840 112.150 57.120 ;
    END
  END S1END[0]
  PIN S1END[1]
    DIRECTION INPUT ;
    USE SIGNAL ;
    ANTENNAGATEAREA 0.318000 ;
    PORT
      LAYER met2 ;
        RECT 113.710 56.840 113.990 57.120 ;
    END
  END S1END[1]
  PIN S1END[2]
    DIRECTION INPUT ;
    USE SIGNAL ;
    ANTENNAGATEAREA 0.318000 ;
    PORT
      LAYER met2 ;
        RECT 115.550 56.840 115.830 57.120 ;
    END
  END S1END[2]
  PIN S1END[3]
    DIRECTION INPUT ;
    USE SIGNAL ;
    ANTENNAGATEAREA 0.318000 ;
    PORT
      LAYER met2 ;
        RECT 117.390 56.840 117.670 57.120 ;
    END
  END S1END[3]
  PIN S2END[0]
    DIRECTION INPUT ;
    USE SIGNAL ;
    ANTENNAGATEAREA 0.159000 ;
    PORT
      LAYER met2 ;
        RECT 133.950 56.840 134.230 57.120 ;
    END
  END S2END[0]
  PIN S2END[1]
    DIRECTION INPUT ;
    USE SIGNAL ;
    ANTENNAGATEAREA 0.159000 ;
    PORT
      LAYER met2 ;
        RECT 135.790 56.840 136.070 57.120 ;
    END
  END S2END[1]
  PIN S2END[2]
    DIRECTION INPUT ;
    USE SIGNAL ;
    ANTENNAGATEAREA 0.159000 ;
    PORT
      LAYER met2 ;
        RECT 137.630 56.840 137.910 57.120 ;
    END
  END S2END[2]
  PIN S2END[3]
    DIRECTION INPUT ;
    USE SIGNAL ;
    ANTENNAGATEAREA 0.159000 ;
    PORT
      LAYER met2 ;
        RECT 139.470 56.840 139.750 57.120 ;
    END
  END S2END[3]
  PIN S2END[4]
    DIRECTION INPUT ;
    USE SIGNAL ;
    ANTENNAGATEAREA 0.318000 ;
    PORT
      LAYER met2 ;
        RECT 141.310 56.840 141.590 57.120 ;
    END
  END S2END[4]
  PIN S2END[5]
    DIRECTION INPUT ;
    USE SIGNAL ;
    ANTENNAGATEAREA 0.318000 ;
    PORT
      LAYER met2 ;
        RECT 143.150 56.840 143.430 57.120 ;
    END
  END S2END[5]
  PIN S2END[6]
    DIRECTION INPUT ;
    USE SIGNAL ;
    ANTENNAGATEAREA 0.318000 ;
    PORT
      LAYER met2 ;
        RECT 144.990 56.840 145.270 57.120 ;
    END
  END S2END[6]
  PIN S2END[7]
    DIRECTION INPUT ;
    USE SIGNAL ;
    ANTENNAGATEAREA 0.318000 ;
    PORT
      LAYER met2 ;
        RECT 146.830 56.840 147.110 57.120 ;
    END
  END S2END[7]
  PIN S2MID[0]
    DIRECTION INPUT ;
    USE SIGNAL ;
    ANTENNAGATEAREA 0.159000 ;
    PORT
      LAYER met2 ;
        RECT 119.230 56.840 119.510 57.120 ;
    END
  END S2MID[0]
  PIN S2MID[1]
    DIRECTION INPUT ;
    USE SIGNAL ;
    ANTENNAGATEAREA 0.593700 ;
    ANTENNADIFFAREA 0.434700 ;
    PORT
      LAYER met2 ;
        RECT 121.070 56.840 121.350 57.120 ;
    END
  END S2MID[1]
  PIN S2MID[2]
    DIRECTION INPUT ;
    USE SIGNAL ;
    ANTENNAGATEAREA 0.593700 ;
    ANTENNADIFFAREA 0.434700 ;
    PORT
      LAYER met2 ;
        RECT 122.910 56.840 123.190 57.120 ;
    END
  END S2MID[2]
  PIN S2MID[3]
    DIRECTION INPUT ;
    USE SIGNAL ;
    ANTENNAGATEAREA 0.159000 ;
    PORT
      LAYER met2 ;
        RECT 124.750 56.840 125.030 57.120 ;
    END
  END S2MID[3]
  PIN S2MID[4]
    DIRECTION INPUT ;
    USE SIGNAL ;
    ANTENNAGATEAREA 0.593700 ;
    ANTENNADIFFAREA 0.434700 ;
    PORT
      LAYER met2 ;
        RECT 126.590 56.840 126.870 57.120 ;
    END
  END S2MID[4]
  PIN S2MID[5]
    DIRECTION INPUT ;
    USE SIGNAL ;
    ANTENNAGATEAREA 0.159000 ;
    PORT
      LAYER met2 ;
        RECT 128.430 56.840 128.710 57.120 ;
    END
  END S2MID[5]
  PIN S2MID[6]
    DIRECTION INPUT ;
    USE SIGNAL ;
    ANTENNAGATEAREA 0.159000 ;
    PORT
      LAYER met2 ;
        RECT 130.270 56.840 130.550 57.120 ;
    END
  END S2MID[6]
  PIN S2MID[7]
    DIRECTION INPUT ;
    USE SIGNAL ;
    ANTENNAGATEAREA 0.593700 ;
    ANTENNADIFFAREA 0.434700 ;
    PORT
      LAYER met2 ;
        RECT 132.110 56.840 132.390 57.120 ;
    END
  END S2MID[7]
  PIN S4END[0]
    DIRECTION INPUT ;
    USE SIGNAL ;
    ANTENNAGATEAREA 0.318000 ;
    PORT
      LAYER met2 ;
        RECT 148.670 56.840 148.950 57.120 ;
    END
  END S4END[0]
  PIN S4END[10]
    DIRECTION INPUT ;
    USE SIGNAL ;
    ANTENNAGATEAREA 0.159000 ;
    PORT
      LAYER met2 ;
        RECT 167.070 56.840 167.350 57.120 ;
    END
  END S4END[10]
  PIN S4END[11]
    DIRECTION INPUT ;
    USE SIGNAL ;
    ANTENNAGATEAREA 0.159000 ;
    PORT
      LAYER met2 ;
        RECT 168.910 56.840 169.190 57.120 ;
    END
  END S4END[11]
  PIN S4END[12]
    DIRECTION INPUT ;
    USE SIGNAL ;
    ANTENNAGATEAREA 0.159000 ;
    PORT
      LAYER met2 ;
        RECT 170.750 56.840 171.030 57.120 ;
    END
  END S4END[12]
  PIN S4END[13]
    DIRECTION INPUT ;
    USE SIGNAL ;
    ANTENNAGATEAREA 0.159000 ;
    PORT
      LAYER met2 ;
        RECT 172.590 56.840 172.870 57.120 ;
    END
  END S4END[13]
  PIN S4END[14]
    DIRECTION INPUT ;
    USE SIGNAL ;
    ANTENNAGATEAREA 0.159000 ;
    PORT
      LAYER met2 ;
        RECT 174.430 56.840 174.710 57.120 ;
    END
  END S4END[14]
  PIN S4END[15]
    DIRECTION INPUT ;
    USE SIGNAL ;
    ANTENNAGATEAREA 0.159000 ;
    PORT
      LAYER met2 ;
        RECT 176.270 56.840 176.550 57.120 ;
    END
  END S4END[15]
  PIN S4END[1]
    DIRECTION INPUT ;
    USE SIGNAL ;
    ANTENNAGATEAREA 0.318000 ;
    PORT
      LAYER met2 ;
        RECT 150.510 56.840 150.790 57.120 ;
    END
  END S4END[1]
  PIN S4END[2]
    DIRECTION INPUT ;
    USE SIGNAL ;
    ANTENNAGATEAREA 0.318000 ;
    PORT
      LAYER met2 ;
        RECT 152.350 56.840 152.630 57.120 ;
    END
  END S4END[2]
  PIN S4END[3]
    DIRECTION INPUT ;
    USE SIGNAL ;
    ANTENNAGATEAREA 0.318000 ;
    PORT
      LAYER met2 ;
        RECT 154.190 56.840 154.470 57.120 ;
    END
  END S4END[3]
  PIN S4END[4]
    DIRECTION INPUT ;
    USE SIGNAL ;
    ANTENNAGATEAREA 0.159000 ;
    PORT
      LAYER met2 ;
        RECT 156.030 56.840 156.310 57.120 ;
    END
  END S4END[4]
  PIN S4END[5]
    DIRECTION INPUT ;
    USE SIGNAL ;
    ANTENNAGATEAREA 0.159000 ;
    PORT
      LAYER met2 ;
        RECT 157.870 56.840 158.150 57.120 ;
    END
  END S4END[5]
  PIN S4END[6]
    DIRECTION INPUT ;
    USE SIGNAL ;
    ANTENNAGATEAREA 0.159000 ;
    PORT
      LAYER met2 ;
        RECT 159.710 56.840 159.990 57.120 ;
    END
  END S4END[6]
  PIN S4END[7]
    DIRECTION INPUT ;
    USE SIGNAL ;
    ANTENNAGATEAREA 0.159000 ;
    PORT
      LAYER met2 ;
        RECT 161.550 56.840 161.830 57.120 ;
    END
  END S4END[7]
  PIN S4END[8]
    DIRECTION INPUT ;
    USE SIGNAL ;
    ANTENNAGATEAREA 0.159000 ;
    PORT
      LAYER met2 ;
        RECT 163.390 56.840 163.670 57.120 ;
    END
  END S4END[8]
  PIN S4END[9]
    DIRECTION INPUT ;
    USE SIGNAL ;
    ANTENNAGATEAREA 0.159000 ;
    PORT
      LAYER met2 ;
        RECT 165.230 56.840 165.510 57.120 ;
    END
  END S4END[9]
  PIN SS4END[0]
    DIRECTION INPUT ;
    USE SIGNAL ;
    ANTENNAGATEAREA 0.159000 ;
    PORT
      LAYER met2 ;
        RECT 178.110 56.840 178.390 57.120 ;
    END
  END SS4END[0]
  PIN SS4END[10]
    DIRECTION INPUT ;
    USE SIGNAL ;
    ANTENNAGATEAREA 0.159000 ;
    PORT
      LAYER met2 ;
        RECT 196.510 56.840 196.790 57.120 ;
    END
  END SS4END[10]
  PIN SS4END[11]
    DIRECTION INPUT ;
    USE SIGNAL ;
    ANTENNAGATEAREA 0.159000 ;
    PORT
      LAYER met2 ;
        RECT 198.350 56.840 198.630 57.120 ;
    END
  END SS4END[11]
  PIN SS4END[12]
    DIRECTION INPUT ;
    USE SIGNAL ;
    ANTENNAGATEAREA 0.159000 ;
    PORT
      LAYER met2 ;
        RECT 200.190 56.840 200.470 57.120 ;
    END
  END SS4END[12]
  PIN SS4END[13]
    DIRECTION INPUT ;
    USE SIGNAL ;
    ANTENNAGATEAREA 0.159000 ;
    PORT
      LAYER met2 ;
        RECT 202.030 56.840 202.310 57.120 ;
    END
  END SS4END[13]
  PIN SS4END[14]
    DIRECTION INPUT ;
    USE SIGNAL ;
    ANTENNAGATEAREA 0.159000 ;
    PORT
      LAYER met2 ;
        RECT 203.870 56.840 204.150 57.120 ;
    END
  END SS4END[14]
  PIN SS4END[15]
    DIRECTION INPUT ;
    USE SIGNAL ;
    ANTENNAGATEAREA 0.159000 ;
    PORT
      LAYER met2 ;
        RECT 205.710 56.840 205.990 57.120 ;
    END
  END SS4END[15]
  PIN SS4END[1]
    DIRECTION INPUT ;
    USE SIGNAL ;
    ANTENNAGATEAREA 0.159000 ;
    PORT
      LAYER met2 ;
        RECT 179.950 56.840 180.230 57.120 ;
    END
  END SS4END[1]
  PIN SS4END[2]
    DIRECTION INPUT ;
    USE SIGNAL ;
    ANTENNAGATEAREA 0.159000 ;
    PORT
      LAYER met2 ;
        RECT 181.790 56.840 182.070 57.120 ;
    END
  END SS4END[2]
  PIN SS4END[3]
    DIRECTION INPUT ;
    USE SIGNAL ;
    ANTENNAGATEAREA 0.159000 ;
    PORT
      LAYER met2 ;
        RECT 183.630 56.840 183.910 57.120 ;
    END
  END SS4END[3]
  PIN SS4END[4]
    DIRECTION INPUT ;
    USE SIGNAL ;
    ANTENNAGATEAREA 0.159000 ;
    PORT
      LAYER met2 ;
        RECT 185.470 56.840 185.750 57.120 ;
    END
  END SS4END[4]
  PIN SS4END[5]
    DIRECTION INPUT ;
    USE SIGNAL ;
    ANTENNAGATEAREA 0.159000 ;
    PORT
      LAYER met2 ;
        RECT 187.310 56.840 187.590 57.120 ;
    END
  END SS4END[5]
  PIN SS4END[6]
    DIRECTION INPUT ;
    USE SIGNAL ;
    ANTENNAGATEAREA 0.159000 ;
    PORT
      LAYER met2 ;
        RECT 189.150 56.840 189.430 57.120 ;
    END
  END SS4END[6]
  PIN SS4END[7]
    DIRECTION INPUT ;
    USE SIGNAL ;
    ANTENNAGATEAREA 0.159000 ;
    PORT
      LAYER met2 ;
        RECT 190.990 56.840 191.270 57.120 ;
    END
  END SS4END[7]
  PIN SS4END[8]
    DIRECTION INPUT ;
    USE SIGNAL ;
    ANTENNAGATEAREA 0.159000 ;
    PORT
      LAYER met2 ;
        RECT 192.830 56.840 193.110 57.120 ;
    END
  END SS4END[8]
  PIN SS4END[9]
    DIRECTION INPUT ;
    USE SIGNAL ;
    ANTENNAGATEAREA 0.159000 ;
    PORT
      LAYER met2 ;
        RECT 194.670 56.840 194.950 57.120 ;
    END
  END SS4END[9]
  PIN VGND
    DIRECTION INOUT ;
    USE GROUND ;
    PORT
      LAYER met4 ;
        RECT 12.260 0.000 13.860 57.120 ;
    END
    PORT
      LAYER met4 ;
        RECT 42.260 0.000 43.860 57.120 ;
    END
    PORT
      LAYER met4 ;
        RECT 72.260 0.000 73.860 57.120 ;
    END
    PORT
      LAYER met4 ;
        RECT 102.260 0.000 103.860 57.120 ;
    END
    PORT
      LAYER met4 ;
        RECT 132.260 0.000 133.860 57.120 ;
    END
    PORT
      LAYER met4 ;
        RECT 162.260 0.000 163.860 57.120 ;
    END
    PORT
      LAYER met4 ;
        RECT 192.260 0.000 193.860 57.120 ;
    END
    PORT
      LAYER met4 ;
        RECT 222.260 0.000 223.860 57.120 ;
    END
  END VGND
  PIN VPWR
    DIRECTION INOUT ;
    USE POWER ;
    PORT
      LAYER met4 ;
        RECT 6.960 0.000 8.560 57.120 ;
    END
    PORT
      LAYER met4 ;
        RECT 36.960 0.000 38.560 57.120 ;
    END
    PORT
      LAYER met4 ;
        RECT 66.960 0.000 68.560 57.120 ;
    END
    PORT
      LAYER met4 ;
        RECT 96.960 0.000 98.560 57.120 ;
    END
    PORT
      LAYER met4 ;
        RECT 126.960 0.000 128.560 57.120 ;
    END
    PORT
      LAYER met4 ;
        RECT 156.960 0.000 158.560 57.120 ;
    END
    PORT
      LAYER met4 ;
        RECT 186.960 0.000 188.560 57.120 ;
    END
    PORT
      LAYER met4 ;
        RECT 216.960 0.000 218.560 57.120 ;
    END
    PORT
      LAYER met4 ;
        RECT 246.960 0.000 248.560 57.120 ;
    END
  END VPWR
  PIN W_GBUF_FEED_BEG[0]
    DIRECTION OUTPUT ;
    USE SIGNAL ;
    ANTENNADIFFAREA 0.702900 ;
    PORT
      LAYER met3 ;
        RECT 0.000 1.400 0.600 2.000 ;
    END
  END W_GBUF_FEED_BEG[0]
  PIN W_GBUF_FEED_BEG[1]
    DIRECTION OUTPUT ;
    USE SIGNAL ;
    ANTENNADIFFAREA 0.702900 ;
    PORT
      LAYER met3 ;
        RECT 0.000 2.760 0.600 3.360 ;
    END
  END W_GBUF_FEED_BEG[1]
  PIN W_GBUF_FEED_BEG[2]
    DIRECTION OUTPUT ;
    USE SIGNAL ;
    ANTENNADIFFAREA 0.702900 ;
    PORT
      LAYER met3 ;
        RECT 0.000 4.120 0.600 4.720 ;
    END
  END W_GBUF_FEED_BEG[2]
  PIN W_GBUF_FEED_BEG[3]
    DIRECTION OUTPUT ;
    USE SIGNAL ;
    ANTENNADIFFAREA 0.702900 ;
    PORT
      LAYER met3 ;
        RECT 0.000 5.480 0.600 6.080 ;
    END
  END W_GBUF_FEED_BEG[3]
  PIN W_GBUF_FEED_END[0]
    DIRECTION INPUT ;
    USE SIGNAL ;
    ANTENNAGATEAREA 0.593700 ;
    ANTENNADIFFAREA 0.434700 ;
    PORT
      LAYER met3 ;
        RECT 251.480 1.400 252.080 2.000 ;
    END
  END W_GBUF_FEED_END[0]
  PIN W_GBUF_FEED_END[1]
    DIRECTION INPUT ;
    USE SIGNAL ;
    ANTENNAGATEAREA 0.593700 ;
    ANTENNADIFFAREA 0.434700 ;
    PORT
      LAYER met3 ;
        RECT 251.480 2.760 252.080 3.360 ;
    END
  END W_GBUF_FEED_END[1]
  PIN W_GBUF_FEED_END[2]
    DIRECTION INPUT ;
    USE SIGNAL ;
    ANTENNAGATEAREA 0.593700 ;
    ANTENNADIFFAREA 0.434700 ;
    PORT
      LAYER met3 ;
        RECT 251.480 4.120 252.080 4.720 ;
    END
  END W_GBUF_FEED_END[2]
  PIN W_GBUF_FEED_END[3]
    DIRECTION INPUT ;
    USE SIGNAL ;
    ANTENNAGATEAREA 0.593700 ;
    ANTENNADIFFAREA 0.434700 ;
    PORT
      LAYER met3 ;
        RECT 251.480 5.480 252.080 6.080 ;
    END
  END W_GBUF_FEED_END[3]
  OBS
      LAYER nwell ;
        RECT 2.570 2.635 249.510 54.590 ;
      LAYER li1 ;
        RECT 2.760 2.635 249.320 54.485 ;
      LAYER met1 ;
        RECT 0.990 0.380 250.630 56.740 ;
      LAYER met2 ;
        RECT 1.010 56.560 8.550 56.850 ;
        RECT 9.390 56.560 10.390 56.850 ;
        RECT 11.230 56.560 12.230 56.850 ;
        RECT 13.070 56.560 14.070 56.850 ;
        RECT 14.910 56.560 15.910 56.850 ;
        RECT 16.750 56.560 17.750 56.850 ;
        RECT 18.590 56.560 19.590 56.850 ;
        RECT 20.430 56.560 21.430 56.850 ;
        RECT 22.270 56.560 23.270 56.850 ;
        RECT 24.110 56.560 25.110 56.850 ;
        RECT 25.950 56.560 26.950 56.850 ;
        RECT 27.790 56.560 28.790 56.850 ;
        RECT 29.630 56.560 30.630 56.850 ;
        RECT 31.470 56.560 32.470 56.850 ;
        RECT 33.310 56.560 34.310 56.850 ;
        RECT 35.150 56.560 36.150 56.850 ;
        RECT 36.990 56.560 37.990 56.850 ;
        RECT 38.830 56.560 39.830 56.850 ;
        RECT 40.670 56.560 41.670 56.850 ;
        RECT 42.510 56.560 43.510 56.850 ;
        RECT 44.350 56.560 45.350 56.850 ;
        RECT 46.190 56.560 47.190 56.850 ;
        RECT 48.030 56.560 49.030 56.850 ;
        RECT 49.870 56.560 50.870 56.850 ;
        RECT 51.710 56.560 52.710 56.850 ;
        RECT 53.550 56.560 54.550 56.850 ;
        RECT 55.390 56.560 56.390 56.850 ;
        RECT 57.230 56.560 58.230 56.850 ;
        RECT 59.070 56.560 60.070 56.850 ;
        RECT 60.910 56.560 61.910 56.850 ;
        RECT 62.750 56.560 63.750 56.850 ;
        RECT 64.590 56.560 65.590 56.850 ;
        RECT 66.430 56.560 67.430 56.850 ;
        RECT 68.270 56.560 69.270 56.850 ;
        RECT 70.110 56.560 71.110 56.850 ;
        RECT 71.950 56.560 72.950 56.850 ;
        RECT 73.790 56.560 74.790 56.850 ;
        RECT 75.630 56.560 76.630 56.850 ;
        RECT 77.470 56.560 78.470 56.850 ;
        RECT 79.310 56.560 80.310 56.850 ;
        RECT 81.150 56.560 82.150 56.850 ;
        RECT 82.990 56.560 83.990 56.850 ;
        RECT 84.830 56.560 85.830 56.850 ;
        RECT 86.670 56.560 87.670 56.850 ;
        RECT 88.510 56.560 89.510 56.850 ;
        RECT 90.350 56.560 91.350 56.850 ;
        RECT 92.190 56.560 93.190 56.850 ;
        RECT 94.030 56.560 95.030 56.850 ;
        RECT 95.870 56.560 96.870 56.850 ;
        RECT 97.710 56.560 98.710 56.850 ;
        RECT 99.550 56.560 100.550 56.850 ;
        RECT 101.390 56.560 102.390 56.850 ;
        RECT 103.230 56.560 104.230 56.850 ;
        RECT 105.070 56.560 106.070 56.850 ;
        RECT 106.910 56.560 107.910 56.850 ;
        RECT 108.750 56.560 109.750 56.850 ;
        RECT 110.590 56.560 111.590 56.850 ;
        RECT 112.430 56.560 113.430 56.850 ;
        RECT 114.270 56.560 115.270 56.850 ;
        RECT 116.110 56.560 117.110 56.850 ;
        RECT 117.950 56.560 118.950 56.850 ;
        RECT 119.790 56.560 120.790 56.850 ;
        RECT 121.630 56.560 122.630 56.850 ;
        RECT 123.470 56.560 124.470 56.850 ;
        RECT 125.310 56.560 126.310 56.850 ;
        RECT 127.150 56.560 128.150 56.850 ;
        RECT 128.990 56.560 129.990 56.850 ;
        RECT 130.830 56.560 131.830 56.850 ;
        RECT 132.670 56.560 133.670 56.850 ;
        RECT 134.510 56.560 135.510 56.850 ;
        RECT 136.350 56.560 137.350 56.850 ;
        RECT 138.190 56.560 139.190 56.850 ;
        RECT 140.030 56.560 141.030 56.850 ;
        RECT 141.870 56.560 142.870 56.850 ;
        RECT 143.710 56.560 144.710 56.850 ;
        RECT 145.550 56.560 146.550 56.850 ;
        RECT 147.390 56.560 148.390 56.850 ;
        RECT 149.230 56.560 150.230 56.850 ;
        RECT 151.070 56.560 152.070 56.850 ;
        RECT 152.910 56.560 153.910 56.850 ;
        RECT 154.750 56.560 155.750 56.850 ;
        RECT 156.590 56.560 157.590 56.850 ;
        RECT 158.430 56.560 159.430 56.850 ;
        RECT 160.270 56.560 161.270 56.850 ;
        RECT 162.110 56.560 163.110 56.850 ;
        RECT 163.950 56.560 164.950 56.850 ;
        RECT 165.790 56.560 166.790 56.850 ;
        RECT 167.630 56.560 168.630 56.850 ;
        RECT 169.470 56.560 170.470 56.850 ;
        RECT 171.310 56.560 172.310 56.850 ;
        RECT 173.150 56.560 174.150 56.850 ;
        RECT 174.990 56.560 175.990 56.850 ;
        RECT 176.830 56.560 177.830 56.850 ;
        RECT 178.670 56.560 179.670 56.850 ;
        RECT 180.510 56.560 181.510 56.850 ;
        RECT 182.350 56.560 183.350 56.850 ;
        RECT 184.190 56.560 185.190 56.850 ;
        RECT 186.030 56.560 187.030 56.850 ;
        RECT 187.870 56.560 188.870 56.850 ;
        RECT 189.710 56.560 190.710 56.850 ;
        RECT 191.550 56.560 192.550 56.850 ;
        RECT 193.390 56.560 194.390 56.850 ;
        RECT 195.230 56.560 196.230 56.850 ;
        RECT 197.070 56.560 198.070 56.850 ;
        RECT 198.910 56.560 199.910 56.850 ;
        RECT 200.750 56.560 201.750 56.850 ;
        RECT 202.590 56.560 203.590 56.850 ;
        RECT 204.430 56.560 205.430 56.850 ;
        RECT 206.270 56.560 207.270 56.850 ;
        RECT 208.110 56.560 209.110 56.850 ;
        RECT 209.950 56.560 210.950 56.850 ;
        RECT 211.790 56.560 212.790 56.850 ;
        RECT 213.630 56.560 214.630 56.850 ;
        RECT 215.470 56.560 216.470 56.850 ;
        RECT 217.310 56.560 218.310 56.850 ;
        RECT 219.150 56.560 220.150 56.850 ;
        RECT 220.990 56.560 221.990 56.850 ;
        RECT 222.830 56.560 223.830 56.850 ;
        RECT 224.670 56.560 225.670 56.850 ;
        RECT 226.510 56.560 227.510 56.850 ;
        RECT 228.350 56.560 229.350 56.850 ;
        RECT 230.190 56.560 231.190 56.850 ;
        RECT 232.030 56.560 233.030 56.850 ;
        RECT 233.870 56.560 234.870 56.850 ;
        RECT 235.710 56.560 236.710 56.850 ;
        RECT 237.550 56.560 238.550 56.850 ;
        RECT 239.390 56.560 240.390 56.850 ;
        RECT 241.230 56.560 242.230 56.850 ;
        RECT 243.070 56.560 250.610 56.850 ;
        RECT 1.010 0.560 250.610 56.560 ;
        RECT 1.010 0.270 7.630 0.560 ;
        RECT 8.470 0.270 20.050 0.560 ;
        RECT 20.890 0.270 32.470 0.560 ;
        RECT 33.310 0.270 44.890 0.560 ;
        RECT 45.730 0.270 57.310 0.560 ;
        RECT 58.150 0.270 69.730 0.560 ;
        RECT 70.570 0.270 82.150 0.560 ;
        RECT 82.990 0.270 94.570 0.560 ;
        RECT 95.410 0.270 106.990 0.560 ;
        RECT 107.830 0.270 119.410 0.560 ;
        RECT 120.250 0.270 131.830 0.560 ;
        RECT 132.670 0.270 144.250 0.560 ;
        RECT 145.090 0.270 156.670 0.560 ;
        RECT 157.510 0.270 169.090 0.560 ;
        RECT 169.930 0.270 181.510 0.560 ;
        RECT 182.350 0.270 193.930 0.560 ;
        RECT 194.770 0.270 206.350 0.560 ;
        RECT 207.190 0.270 218.770 0.560 ;
        RECT 219.610 0.270 231.190 0.560 ;
        RECT 232.030 0.270 243.610 0.560 ;
        RECT 244.450 0.270 250.610 0.560 ;
      LAYER met3 ;
        RECT 0.600 55.440 251.480 56.265 ;
        RECT 1.000 1.000 251.080 55.440 ;
        RECT 0.600 0.855 251.480 1.000 ;
      LAYER met4 ;
        RECT 100.575 23.295 101.825 52.185 ;
  END
END S_term_RegFile
END LIBRARY

